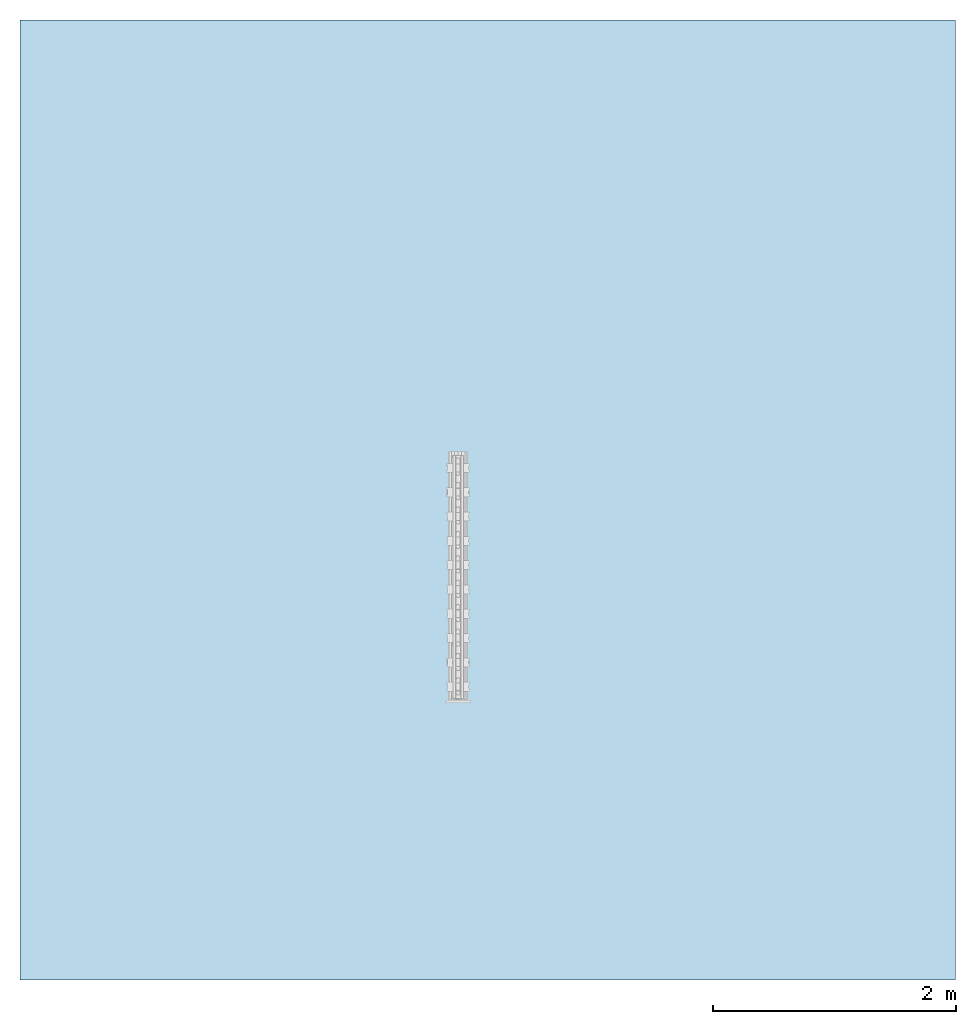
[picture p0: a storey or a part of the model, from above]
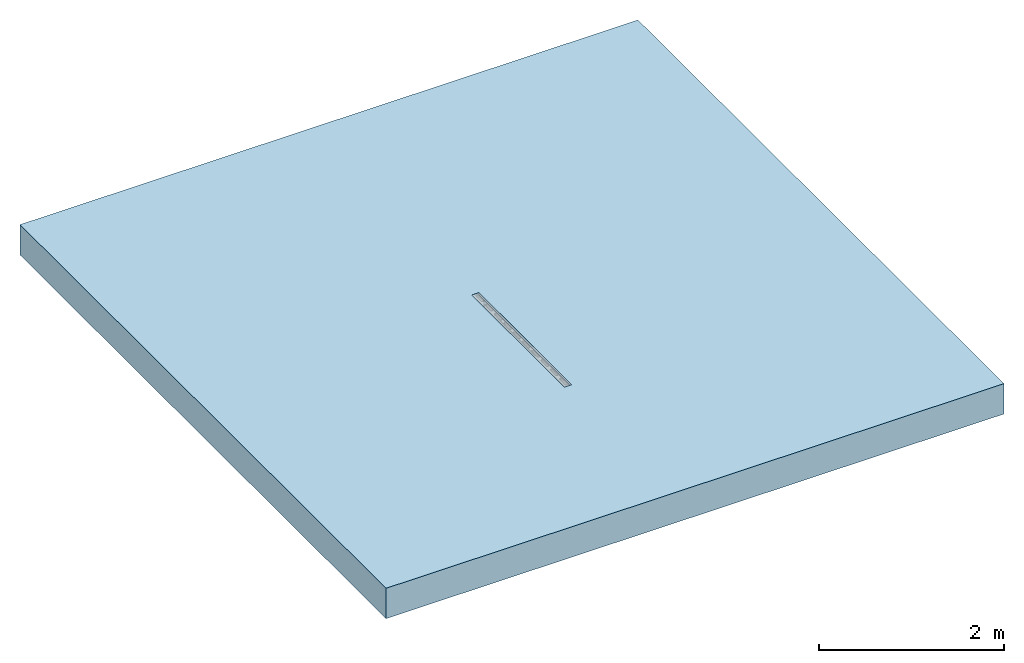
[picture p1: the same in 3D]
Properties of the parts of a building model (IFC2X3)

# File
Description: ViewDefinition [CoordinationView]
File name: 32992 - Q-Flow Edge - G.S.ifc
Time: 2013-08-14T09:26:40
Written by: Autodesk Revit 2013
Made in: 20120221_2030(x64)

# IfcProject, Project Number
LongName: Project Name; Phase: Project Status

# IfcSite, Default
RefLatitude: 42, 21, 30, 344238; RefLongitude: -71, -3, -35, -194702; RefElevation: 0 mm

# IfcBuilding
Pset_BuildingCommon - NumberOfStoreys: 1
Other - Project Name: Project Name; Project Address: ## Street City, State Zip; Project Issue Date: Issue Date; Project Status: Project Status; Client Name: Owner; Project Number: Project Number

# IfcBuildingStorey, Level 1
LongName: Level 1; Elevation: 0 mm
Constraints - Elevation Base: 0; Elevation: 0 mm
Graphics - Line Weight: 1; Symbol at End 2 Default: yes; Color: 0; Symbol at End 1 Default: no; Line Pattern: Center; Symbol: M_Level Head - Circle: M_Level Head - Circle
Identity Data - Name: Level 1; Structural: no; Building Story: yes
Dimensions - Computation Height: 0 mm

# IfcFlowTerminal: 32992 - Q-Flow Edge - G.S, Qmax 150:32992 - Q-Flow Edge - G.S:32992 - Q-Flow Edge - G.S:730922
In: Level 1
Constraints - Level: Level: Level 1; Moves With Nearby Elements: no
Phasing - Phase Created: New Construction
Identity Data - Mark: 77; Installation Guidelines: http://www.aco.co.uk/download.php?id=220; Maintenance Guidelines: http://www.aco.co.uk/download.php?id=220; OmniClass Number: 23.70.50.24; Fax: +44 (0)1462 815895; Model Description: High capacity slot drainage channel system; Cost: 0; Telephone: +44 (0)1462 816666; Model: ACO Qmax 150; Price: POA - contact ACO; URL: www.aco.co.uk; Address: ACO Business Park, Hitchin Road, Shefford, Bedfordshire, United Kingdom SG17 5TE; Assembly Code: D2040; OmniClass Title: Rainwater Removal; Product Brochure: http://www.aco.co.uk/download.php?id=220; Assembly Description: Rain Water Drainage; Type Comments: ACO Qmax 150 channel assembly complete with ACO Q-Flow galvanised steel edge rail; e-mail Sales: customersupport@aco.co.uk; Product Code: 32992; e-mail Technical: technical@aco.co.uk; Manufacturer: ACO Technologies plc - ACO Water Management Division; Product Page URL: http://www.aco.co.uk/product_detail.php?id=79
Construction - 32997_150 End Cap (at Female end): no; 32997_150 End Cap (at Male end): no; E1-QFlow-DuctileIron: no; E5-QSlot-GalvSteel: no; E3-QFlow-GalvSteel: yes; E2-QGuard-DuctileIron: no; V_Coarse_E5: no; E4-QGuard-GalvSteel: no; V_CoarseE1: yes
General - TagNumber: 0; SerialNumber: 0
Materials and Finishes - Seal Colour: Black; Edge Rail Material: Steel; Channel Material: Medium Density Polyethylene; Edge Rail Finish: Galvanised; Seal Material: Chloroprene; Edge Rail Colour: Silver Silver; Channel Colour: Black
Green Building Properties - Channel Recycled Material Content: Variable %; Channel Recyclable: Fully recyclable; Edge Rail Recycled Material Content: Between 40% - 90%; Seal Recycled Material Content: 0%; Seal Recyclable: Fully recyclable; Edge Rail Recyclable: Fully recyclable
Dimensions - Width Overall: 210 mm; Floor Opening Width: 90 mm; TopCoarse: 13 mm; Length: 2000 mm; BoreCentre: 277 mm; Depth Overall: 400 mm
Model Properties - Multi-Functional End Cap - Channel Recyclable: Fully recyclable; Multi-Functional End Cap - Channel Recycled Material Content: Variable %; Multi-Functional End Cap - Weight: 1 kg; Multi-Functional End Cap - Channel Colour: Black; Multi-Functional End Cap - Seal Recycled Material Content: 0%; Multi-Functional End Cap - Dimensions: Ø210mm x 240mm (ØxL); Multi-Functional End Cap - Seal Recyclable: Fully recyclable e; Multi-Functional End Cap - Model Description: High capacity slot drainage channel system; Multi-Functional End Cap - Product Code: 32997; Multi-Functional End Cap - Channel Material: Medium Density Polyethylene; Multi-Functional End Cap - Seal Material: Chloroprene; Multi-Functional End Cap - Seal Colour: Black
Data - Hydraulic Performance: http://www.aco.co.uk/download.php?id=220; Product Weight: 15.8 kg; Invert Depth: 350mm; Channel C.S.A: 17671mm²; Concrete Surround Volume - Load Class E 600: 0.205 m³/m; Installation - Concrete Grade: Refer to brochure; Concrete Surround Volume - Load Class A 15 - D 400: 0.135 m³/m; Drainage Slot Intake Area: 18106mm²/m; Concrete Surround Volume - Load Class F 900: 0.285 m³/m; Drainage Slot Width: 26mm; ACO Hydraulic Design Software: http://www.acodesign.co.uk; Installation - Reinforcement Details: Refer to brochure; Product Dimensions: 2000mm x 210mm x 400mm (LxWxH); Product Standard: BS EN 1433:2002 CE marked; Load Class: A 15 - F 900
Other - Created by: www.aco.co.uk; Revision: 1

# IfcOpeningElement: Opening
In: Level 1
Dimensions - Perimeter: 31200 mm; Area: 60650000 mm2; Volume: 24166760000 mm3; Thickness: 400 mm
Structural - Enable Analytical Model: no; Structural: no
Constraints - Room Bounding: yes; Level: Level: Level 1; Related to Mass: no; Height Offset From Level: 0 mm
Phasing - Phase Created: New Construction
Graphics - Coarse Scale Fill Color: 0
Analytical Properties - Absorptance: 0.1; Roughness: 1
Construction - Default Thickness: 400 mm; Function: 0
Materials and Finishes - Structural Material: Plant

# IfcSlab: Floor:Generic Floor - 400mm, Floor:Generic Floor - 400mm:193825
In: Level 1
PredefinedType: FLOOR; Material: Plant 400 mm
Dimensions - Perimeter: 31200 mm; Area: 60650000 mm2; Volume: 24166760000 mm3; Thickness: 400 mm
Structural - Enable Analytical Model: no; Structural: no
Constraints - Room Bounding: yes; Level: Level: Level 1; Related to Mass: no; Height Offset From Level: 0 mm
Phasing - Phase Created: New Construction
Pset_SlabCommon - Reference: Generic Floor - 400mm; IsExternal: no; LoadBearing: yes
Graphics - Coarse Scale Fill Color: 0
Analytical Properties - Absorptance: 0.1; Roughness: 1
Construction - Default Thickness: 400 mm; Function: 0
Materials and Finishes - Structural Material: Plant
